VERSION 5.8 ;
BUSBITCHARS "[]" ;
DIVIDERCHAR "/" ;
UNITS
    DATABASE MICRONS 1000 ;
END UNITS

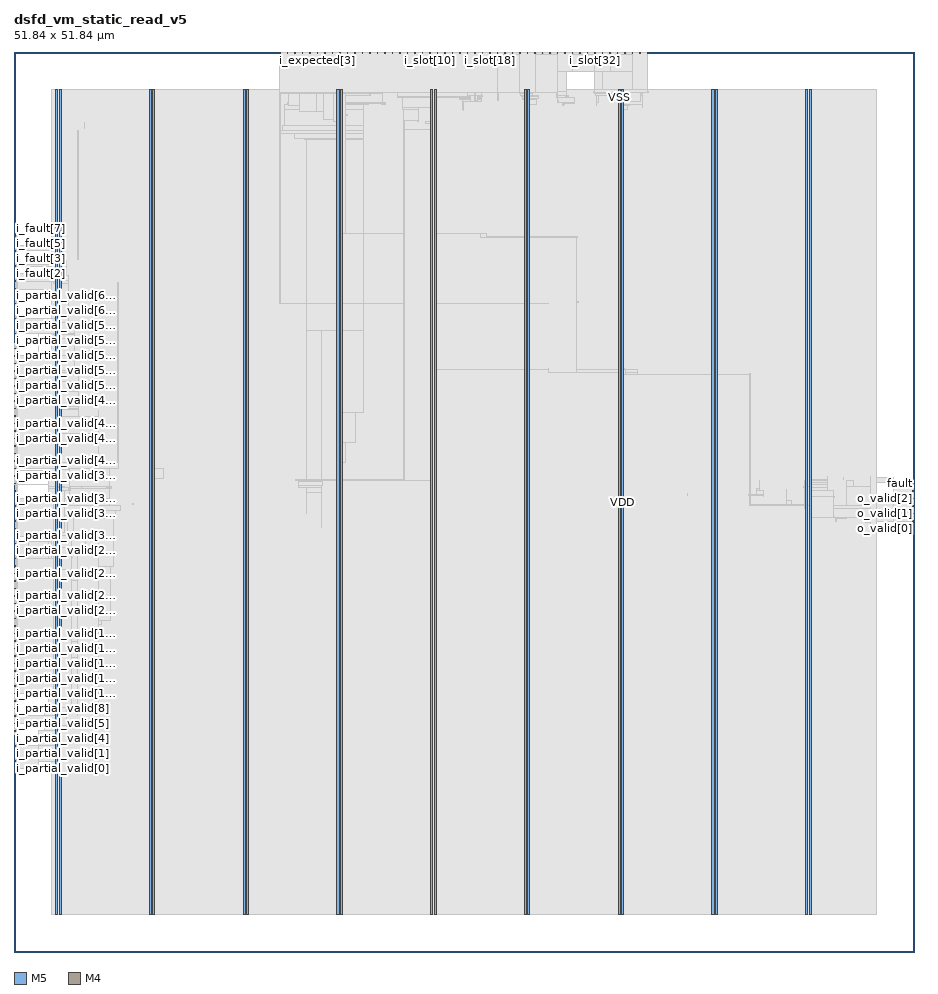
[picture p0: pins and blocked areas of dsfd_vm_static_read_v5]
MACRO dsfd_vm_static_read_v5
  FOREIGN dsfd_vm_static_read_v5 0 0 ;
  CLASS BLOCK ;
  SIZE 51.84 BY 51.84 ;
  PIN ck
    DIRECTION INPUT ;
    USE SIGNAL ;
    PORT
      LAYER M5 ;
        RECT  15.312 51.756 15.336 51.84 ;
    END
  END ck
  PIN fault
    DIRECTION OUTPUT ;
    USE SIGNAL ;
    PORT
      LAYER M4 ;
        RECT  51.756 26.976 51.84 27 ;
    END
  END fault
  PIN i_expected[0]
    DIRECTION INPUT ;
    USE SIGNAL ;
    PORT
      LAYER M5 ;
        RECT  16.176 51.756 16.2 51.84 ;
    END
  END i_expected[0]
  PIN i_expected[1]
    DIRECTION INPUT ;
    USE SIGNAL ;
    PORT
      LAYER M5 ;
        RECT  16.608 51.756 16.632 51.84 ;
    END
  END i_expected[1]
  PIN i_expected[2]
    DIRECTION INPUT ;
    USE SIGNAL ;
    PORT
      LAYER M5 ;
        RECT  17.04 51.756 17.064 51.84 ;
    END
  END i_expected[2]
  PIN i_expected[3]
    DIRECTION INPUT ;
    USE SIGNAL ;
    PORT
      LAYER M5 ;
        RECT  17.472 51.756 17.496 51.84 ;
    END
  END i_expected[3]
  PIN i_expected[4]
    DIRECTION INPUT ;
    USE SIGNAL ;
    PORT
      LAYER M5 ;
        RECT  17.904 51.756 17.928 51.84 ;
    END
  END i_expected[4]
  PIN i_expected[5]
    DIRECTION INPUT ;
    USE SIGNAL ;
    PORT
      LAYER M5 ;
        RECT  18.336 51.756 18.36 51.84 ;
    END
  END i_expected[5]
  PIN i_expected[6]
    DIRECTION INPUT ;
    USE SIGNAL ;
    PORT
      LAYER M5 ;
        RECT  18.768 51.756 18.792 51.84 ;
    END
  END i_expected[6]
  PIN i_expected[7]
    DIRECTION INPUT ;
    USE SIGNAL ;
    PORT
      LAYER M5 ;
        RECT  19.2 51.756 19.224 51.84 ;
    END
  END i_expected[7]
  PIN i_fault[0]
    DIRECTION INPUT ;
    USE SIGNAL ;
    PORT
      LAYER M4 ;
        RECT  0 38.208 0.084 38.232 ;
    END
  END i_fault[0]
  PIN i_fault[1]
    DIRECTION INPUT ;
    USE SIGNAL ;
    PORT
      LAYER M4 ;
        RECT  0 38.64 0.084 38.664 ;
    END
  END i_fault[1]
  PIN i_fault[2]
    DIRECTION INPUT ;
    USE SIGNAL ;
    PORT
      LAYER M4 ;
        RECT  0 39.072 0.084 39.096 ;
    END
  END i_fault[2]
  PIN i_fault[3]
    DIRECTION INPUT ;
    USE SIGNAL ;
    PORT
      LAYER M4 ;
        RECT  0 39.504 0.084 39.528 ;
    END
  END i_fault[3]
  PIN i_fault[4]
    DIRECTION INPUT ;
    USE SIGNAL ;
    PORT
      LAYER M4 ;
        RECT  0 39.936 0.084 39.96 ;
    END
  END i_fault[4]
  PIN i_fault[5]
    DIRECTION INPUT ;
    USE SIGNAL ;
    PORT
      LAYER M4 ;
        RECT  0 40.368 0.084 40.392 ;
    END
  END i_fault[5]
  PIN i_fault[6]
    DIRECTION INPUT ;
    USE SIGNAL ;
    PORT
      LAYER M4 ;
        RECT  0 40.8 0.084 40.824 ;
    END
  END i_fault[6]
  PIN i_fault[7]
    DIRECTION INPUT ;
    USE SIGNAL ;
    PORT
      LAYER M4 ;
        RECT  0 41.232 0.084 41.256 ;
    END
  END i_fault[7]
  PIN i_partial_valid[0]
    DIRECTION INPUT ;
    USE SIGNAL ;
    PORT
      LAYER M4 ;
        RECT  0 10.56 0.084 10.584 ;
    END
  END i_partial_valid[0]
  PIN i_partial_valid[10]
    DIRECTION INPUT ;
    USE SIGNAL ;
    PORT
      LAYER M4 ;
        RECT  0 14.88 0.084 14.904 ;
    END
  END i_partial_valid[10]
  PIN i_partial_valid[11]
    DIRECTION INPUT ;
    USE SIGNAL ;
    PORT
      LAYER M4 ;
        RECT  0 15.312 0.084 15.336 ;
    END
  END i_partial_valid[11]
  PIN i_partial_valid[12]
    DIRECTION INPUT ;
    USE SIGNAL ;
    PORT
      LAYER M4 ;
        RECT  0 15.744 0.084 15.768 ;
    END
  END i_partial_valid[12]
  PIN i_partial_valid[13]
    DIRECTION INPUT ;
    USE SIGNAL ;
    PORT
      LAYER M4 ;
        RECT  0 16.176 0.084 16.2 ;
    END
  END i_partial_valid[13]
  PIN i_partial_valid[14]
    DIRECTION INPUT ;
    USE SIGNAL ;
    PORT
      LAYER M4 ;
        RECT  0 16.608 0.084 16.632 ;
    END
  END i_partial_valid[14]
  PIN i_partial_valid[15]
    DIRECTION INPUT ;
    USE SIGNAL ;
    PORT
      LAYER M4 ;
        RECT  0 17.04 0.084 17.064 ;
    END
  END i_partial_valid[15]
  PIN i_partial_valid[16]
    DIRECTION INPUT ;
    USE SIGNAL ;
    PORT
      LAYER M4 ;
        RECT  0 17.472 0.084 17.496 ;
    END
  END i_partial_valid[16]
  PIN i_partial_valid[17]
    DIRECTION INPUT ;
    USE SIGNAL ;
    PORT
      LAYER M4 ;
        RECT  0 17.904 0.084 17.928 ;
    END
  END i_partial_valid[17]
  PIN i_partial_valid[18]
    DIRECTION INPUT ;
    USE SIGNAL ;
    PORT
      LAYER M4 ;
        RECT  0 18.336 0.084 18.36 ;
    END
  END i_partial_valid[18]
  PIN i_partial_valid[19]
    DIRECTION INPUT ;
    USE SIGNAL ;
    PORT
      LAYER M4 ;
        RECT  0 18.768 0.084 18.792 ;
    END
  END i_partial_valid[19]
  PIN i_partial_valid[1]
    DIRECTION INPUT ;
    USE SIGNAL ;
    PORT
      LAYER M4 ;
        RECT  0 10.992 0.084 11.016 ;
    END
  END i_partial_valid[1]
  PIN i_partial_valid[20]
    DIRECTION INPUT ;
    USE SIGNAL ;
    PORT
      LAYER M4 ;
        RECT  0 19.2 0.084 19.224 ;
    END
  END i_partial_valid[20]
  PIN i_partial_valid[21]
    DIRECTION INPUT ;
    USE SIGNAL ;
    PORT
      LAYER M4 ;
        RECT  0 19.632 0.084 19.656 ;
    END
  END i_partial_valid[21]
  PIN i_partial_valid[22]
    DIRECTION INPUT ;
    USE SIGNAL ;
    PORT
      LAYER M4 ;
        RECT  0 20.064 0.084 20.088 ;
    END
  END i_partial_valid[22]
  PIN i_partial_valid[23]
    DIRECTION INPUT ;
    USE SIGNAL ;
    PORT
      LAYER M4 ;
        RECT  0 20.496 0.084 20.52 ;
    END
  END i_partial_valid[23]
  PIN i_partial_valid[24]
    DIRECTION INPUT ;
    USE SIGNAL ;
    PORT
      LAYER M4 ;
        RECT  0 20.928 0.084 20.952 ;
    END
  END i_partial_valid[24]
  PIN i_partial_valid[25]
    DIRECTION INPUT ;
    USE SIGNAL ;
    PORT
      LAYER M4 ;
        RECT  0 21.36 0.084 21.384 ;
    END
  END i_partial_valid[25]
  PIN i_partial_valid[26]
    DIRECTION INPUT ;
    USE SIGNAL ;
    PORT
      LAYER M4 ;
        RECT  0 21.792 0.084 21.816 ;
    END
  END i_partial_valid[26]
  PIN i_partial_valid[27]
    DIRECTION INPUT ;
    USE SIGNAL ;
    PORT
      LAYER M4 ;
        RECT  0 22.224 0.084 22.248 ;
    END
  END i_partial_valid[27]
  PIN i_partial_valid[28]
    DIRECTION INPUT ;
    USE SIGNAL ;
    PORT
      LAYER M4 ;
        RECT  0 22.656 0.084 22.68 ;
    END
  END i_partial_valid[28]
  PIN i_partial_valid[29]
    DIRECTION INPUT ;
    USE SIGNAL ;
    PORT
      LAYER M4 ;
        RECT  0 23.088 0.084 23.112 ;
    END
  END i_partial_valid[29]
  PIN i_partial_valid[2]
    DIRECTION INPUT ;
    USE SIGNAL ;
    PORT
      LAYER M4 ;
        RECT  0 11.424 0.084 11.448 ;
    END
  END i_partial_valid[2]
  PIN i_partial_valid[30]
    DIRECTION INPUT ;
    USE SIGNAL ;
    PORT
      LAYER M4 ;
        RECT  0 23.52 0.084 23.544 ;
    END
  END i_partial_valid[30]
  PIN i_partial_valid[31]
    DIRECTION INPUT ;
    USE SIGNAL ;
    PORT
      LAYER M4 ;
        RECT  0 23.952 0.084 23.976 ;
    END
  END i_partial_valid[31]
  PIN i_partial_valid[32]
    DIRECTION INPUT ;
    USE SIGNAL ;
    PORT
      LAYER M4 ;
        RECT  0 24.384 0.084 24.408 ;
    END
  END i_partial_valid[32]
  PIN i_partial_valid[33]
    DIRECTION INPUT ;
    USE SIGNAL ;
    PORT
      LAYER M4 ;
        RECT  0 24.816 0.084 24.84 ;
    END
  END i_partial_valid[33]
  PIN i_partial_valid[34]
    DIRECTION INPUT ;
    USE SIGNAL ;
    PORT
      LAYER M4 ;
        RECT  0 25.248 0.084 25.272 ;
    END
  END i_partial_valid[34]
  PIN i_partial_valid[35]
    DIRECTION INPUT ;
    USE SIGNAL ;
    PORT
      LAYER M4 ;
        RECT  0 25.68 0.084 25.704 ;
    END
  END i_partial_valid[35]
  PIN i_partial_valid[36]
    DIRECTION INPUT ;
    USE SIGNAL ;
    PORT
      LAYER M4 ;
        RECT  0 26.112 0.084 26.136 ;
    END
  END i_partial_valid[36]
  PIN i_partial_valid[37]
    DIRECTION INPUT ;
    USE SIGNAL ;
    PORT
      LAYER M4 ;
        RECT  0 26.544 0.084 26.568 ;
    END
  END i_partial_valid[37]
  PIN i_partial_valid[38]
    DIRECTION INPUT ;
    USE SIGNAL ;
    PORT
      LAYER M4 ;
        RECT  0 26.976 0.084 27 ;
    END
  END i_partial_valid[38]
  PIN i_partial_valid[39]
    DIRECTION INPUT ;
    USE SIGNAL ;
    PORT
      LAYER M4 ;
        RECT  0 27.408 0.084 27.432 ;
    END
  END i_partial_valid[39]
  PIN i_partial_valid[3]
    DIRECTION INPUT ;
    USE SIGNAL ;
    PORT
      LAYER M4 ;
        RECT  0 11.856 0.084 11.88 ;
    END
  END i_partial_valid[3]
  PIN i_partial_valid[40]
    DIRECTION INPUT ;
    USE SIGNAL ;
    PORT
      LAYER M4 ;
        RECT  0 27.84 0.084 27.864 ;
    END
  END i_partial_valid[40]
  PIN i_partial_valid[41]
    DIRECTION INPUT ;
    USE SIGNAL ;
    PORT
      LAYER M4 ;
        RECT  0 28.272 0.084 28.296 ;
    END
  END i_partial_valid[41]
  PIN i_partial_valid[42]
    DIRECTION INPUT ;
    USE SIGNAL ;
    PORT
      LAYER M4 ;
        RECT  0 28.704 0.084 28.728 ;
    END
  END i_partial_valid[42]
  PIN i_partial_valid[43]
    DIRECTION INPUT ;
    USE SIGNAL ;
    PORT
      LAYER M4 ;
        RECT  0 29.136 0.084 29.16 ;
    END
  END i_partial_valid[43]
  PIN i_partial_valid[44]
    DIRECTION INPUT ;
    USE SIGNAL ;
    PORT
      LAYER M4 ;
        RECT  0 29.568 0.084 29.592 ;
    END
  END i_partial_valid[44]
  PIN i_partial_valid[45]
    DIRECTION INPUT ;
    USE SIGNAL ;
    PORT
      LAYER M4 ;
        RECT  0 30 0.084 30.024 ;
    END
  END i_partial_valid[45]
  PIN i_partial_valid[46]
    DIRECTION INPUT ;
    USE SIGNAL ;
    PORT
      LAYER M4 ;
        RECT  0 30.432 0.084 30.456 ;
    END
  END i_partial_valid[46]
  PIN i_partial_valid[47]
    DIRECTION INPUT ;
    USE SIGNAL ;
    PORT
      LAYER M4 ;
        RECT  0 30.864 0.084 30.888 ;
    END
  END i_partial_valid[47]
  PIN i_partial_valid[48]
    DIRECTION INPUT ;
    USE SIGNAL ;
    PORT
      LAYER M4 ;
        RECT  0 31.296 0.084 31.32 ;
    END
  END i_partial_valid[48]
  PIN i_partial_valid[49]
    DIRECTION INPUT ;
    USE SIGNAL ;
    PORT
      LAYER M4 ;
        RECT  0 31.728 0.084 31.752 ;
    END
  END i_partial_valid[49]
  PIN i_partial_valid[4]
    DIRECTION INPUT ;
    USE SIGNAL ;
    PORT
      LAYER M4 ;
        RECT  0 12.288 0.084 12.312 ;
    END
  END i_partial_valid[4]
  PIN i_partial_valid[50]
    DIRECTION INPUT ;
    USE SIGNAL ;
    PORT
      LAYER M4 ;
        RECT  0 32.16 0.084 32.184 ;
    END
  END i_partial_valid[50]
  PIN i_partial_valid[51]
    DIRECTION INPUT ;
    USE SIGNAL ;
    PORT
      LAYER M4 ;
        RECT  0 32.592 0.084 32.616 ;
    END
  END i_partial_valid[51]
  PIN i_partial_valid[52]
    DIRECTION INPUT ;
    USE SIGNAL ;
    PORT
      LAYER M4 ;
        RECT  0 33.024 0.084 33.048 ;
    END
  END i_partial_valid[52]
  PIN i_partial_valid[53]
    DIRECTION INPUT ;
    USE SIGNAL ;
    PORT
      LAYER M4 ;
        RECT  0 33.456 0.084 33.48 ;
    END
  END i_partial_valid[53]
  PIN i_partial_valid[54]
    DIRECTION INPUT ;
    USE SIGNAL ;
    PORT
      LAYER M4 ;
        RECT  0 33.888 0.084 33.912 ;
    END
  END i_partial_valid[54]
  PIN i_partial_valid[55]
    DIRECTION INPUT ;
    USE SIGNAL ;
    PORT
      LAYER M4 ;
        RECT  0 34.32 0.084 34.344 ;
    END
  END i_partial_valid[55]
  PIN i_partial_valid[56]
    DIRECTION INPUT ;
    USE SIGNAL ;
    PORT
      LAYER M4 ;
        RECT  0 34.752 0.084 34.776 ;
    END
  END i_partial_valid[56]
  PIN i_partial_valid[57]
    DIRECTION INPUT ;
    USE SIGNAL ;
    PORT
      LAYER M4 ;
        RECT  0 35.184 0.084 35.208 ;
    END
  END i_partial_valid[57]
  PIN i_partial_valid[58]
    DIRECTION INPUT ;
    USE SIGNAL ;
    PORT
      LAYER M4 ;
        RECT  0 35.616 0.084 35.64 ;
    END
  END i_partial_valid[58]
  PIN i_partial_valid[59]
    DIRECTION INPUT ;
    USE SIGNAL ;
    PORT
      LAYER M4 ;
        RECT  0 36.048 0.084 36.072 ;
    END
  END i_partial_valid[59]
  PIN i_partial_valid[5]
    DIRECTION INPUT ;
    USE SIGNAL ;
    PORT
      LAYER M4 ;
        RECT  0 12.72 0.084 12.744 ;
    END
  END i_partial_valid[5]
  PIN i_partial_valid[60]
    DIRECTION INPUT ;
    USE SIGNAL ;
    PORT
      LAYER M4 ;
        RECT  0 36.48 0.084 36.504 ;
    END
  END i_partial_valid[60]
  PIN i_partial_valid[61]
    DIRECTION INPUT ;
    USE SIGNAL ;
    PORT
      LAYER M4 ;
        RECT  0 36.912 0.084 36.936 ;
    END
  END i_partial_valid[61]
  PIN i_partial_valid[62]
    DIRECTION INPUT ;
    USE SIGNAL ;
    PORT
      LAYER M4 ;
        RECT  0 37.344 0.084 37.368 ;
    END
  END i_partial_valid[62]
  PIN i_partial_valid[63]
    DIRECTION INPUT ;
    USE SIGNAL ;
    PORT
      LAYER M4 ;
        RECT  0 37.776 0.084 37.8 ;
    END
  END i_partial_valid[63]
  PIN i_partial_valid[6]
    DIRECTION INPUT ;
    USE SIGNAL ;
    PORT
      LAYER M4 ;
        RECT  0 13.152 0.084 13.176 ;
    END
  END i_partial_valid[6]
  PIN i_partial_valid[7]
    DIRECTION INPUT ;
    USE SIGNAL ;
    PORT
      LAYER M4 ;
        RECT  0 13.584 0.084 13.608 ;
    END
  END i_partial_valid[7]
  PIN i_partial_valid[8]
    DIRECTION INPUT ;
    USE SIGNAL ;
    PORT
      LAYER M4 ;
        RECT  0 14.016 0.084 14.04 ;
    END
  END i_partial_valid[8]
  PIN i_partial_valid[9]
    DIRECTION INPUT ;
    USE SIGNAL ;
    PORT
      LAYER M4 ;
        RECT  0 14.448 0.084 14.472 ;
    END
  END i_partial_valid[9]
  PIN i_slot[0]
    DIRECTION INPUT ;
    USE SIGNAL ;
    PORT
      LAYER M5 ;
        RECT  19.632 51.756 19.656 51.84 ;
    END
  END i_slot[0]
  PIN i_slot[10]
    DIRECTION INPUT ;
    USE SIGNAL ;
    PORT
      LAYER M5 ;
        RECT  23.952 51.756 23.976 51.84 ;
    END
  END i_slot[10]
  PIN i_slot[11]
    DIRECTION INPUT ;
    USE SIGNAL ;
    PORT
      LAYER M5 ;
        RECT  24.384 51.756 24.408 51.84 ;
    END
  END i_slot[11]
  PIN i_slot[12]
    DIRECTION INPUT ;
    USE SIGNAL ;
    PORT
      LAYER M5 ;
        RECT  24.816 51.756 24.84 51.84 ;
    END
  END i_slot[12]
  PIN i_slot[13]
    DIRECTION INPUT ;
    USE SIGNAL ;
    PORT
      LAYER M5 ;
        RECT  25.248 51.756 25.272 51.84 ;
    END
  END i_slot[13]
  PIN i_slot[14]
    DIRECTION INPUT ;
    USE SIGNAL ;
    PORT
      LAYER M5 ;
        RECT  25.68 51.756 25.704 51.84 ;
    END
  END i_slot[14]
  PIN i_slot[15]
    DIRECTION INPUT ;
    USE SIGNAL ;
    PORT
      LAYER M5 ;
        RECT  26.112 51.756 26.136 51.84 ;
    END
  END i_slot[15]
  PIN i_slot[16]
    DIRECTION INPUT ;
    USE SIGNAL ;
    PORT
      LAYER M5 ;
        RECT  26.544 51.756 26.568 51.84 ;
    END
  END i_slot[16]
  PIN i_slot[17]
    DIRECTION INPUT ;
    USE SIGNAL ;
    PORT
      LAYER M5 ;
        RECT  26.976 51.756 27 51.84 ;
    END
  END i_slot[17]
  PIN i_slot[18]
    DIRECTION INPUT ;
    USE SIGNAL ;
    PORT
      LAYER M5 ;
        RECT  27.408 51.756 27.432 51.84 ;
    END
  END i_slot[18]
  PIN i_slot[19]
    DIRECTION INPUT ;
    USE SIGNAL ;
    PORT
      LAYER M5 ;
        RECT  27.84 51.756 27.864 51.84 ;
    END
  END i_slot[19]
  PIN i_slot[1]
    DIRECTION INPUT ;
    USE SIGNAL ;
    PORT
      LAYER M5 ;
        RECT  20.064 51.756 20.088 51.84 ;
    END
  END i_slot[1]
  PIN i_slot[20]
    DIRECTION INPUT ;
    USE SIGNAL ;
    PORT
      LAYER M5 ;
        RECT  28.272 51.756 28.296 51.84 ;
    END
  END i_slot[20]
  PIN i_slot[21]
    DIRECTION INPUT ;
    USE SIGNAL ;
    PORT
      LAYER M5 ;
        RECT  28.704 51.756 28.728 51.84 ;
    END
  END i_slot[21]
  PIN i_slot[22]
    DIRECTION INPUT ;
    USE SIGNAL ;
    PORT
      LAYER M5 ;
        RECT  29.136 51.756 29.16 51.84 ;
    END
  END i_slot[22]
  PIN i_slot[23]
    DIRECTION INPUT ;
    USE SIGNAL ;
    PORT
      LAYER M5 ;
        RECT  29.568 51.756 29.592 51.84 ;
    END
  END i_slot[23]
  PIN i_slot[24]
    DIRECTION INPUT ;
    USE SIGNAL ;
    PORT
      LAYER M5 ;
        RECT  30 51.756 30.024 51.84 ;
    END
  END i_slot[24]
  PIN i_slot[25]
    DIRECTION INPUT ;
    USE SIGNAL ;
    PORT
      LAYER M5 ;
        RECT  30.432 51.756 30.456 51.84 ;
    END
  END i_slot[25]
  PIN i_slot[26]
    DIRECTION INPUT ;
    USE SIGNAL ;
    PORT
      LAYER M5 ;
        RECT  30.864 51.756 30.888 51.84 ;
    END
  END i_slot[26]
  PIN i_slot[27]
    DIRECTION INPUT ;
    USE SIGNAL ;
    PORT
      LAYER M5 ;
        RECT  31.296 51.756 31.32 51.84 ;
    END
  END i_slot[27]
  PIN i_slot[28]
    DIRECTION INPUT ;
    USE SIGNAL ;
    PORT
      LAYER M5 ;
        RECT  31.728 51.756 31.752 51.84 ;
    END
  END i_slot[28]
  PIN i_slot[29]
    DIRECTION INPUT ;
    USE SIGNAL ;
    PORT
      LAYER M5 ;
        RECT  32.16 51.756 32.184 51.84 ;
    END
  END i_slot[29]
  PIN i_slot[2]
    DIRECTION INPUT ;
    USE SIGNAL ;
    PORT
      LAYER M5 ;
        RECT  20.496 51.756 20.52 51.84 ;
    END
  END i_slot[2]
  PIN i_slot[30]
    DIRECTION INPUT ;
    USE SIGNAL ;
    PORT
      LAYER M5 ;
        RECT  32.592 51.756 32.616 51.84 ;
    END
  END i_slot[30]
  PIN i_slot[31]
    DIRECTION INPUT ;
    USE SIGNAL ;
    PORT
      LAYER M5 ;
        RECT  33.024 51.756 33.048 51.84 ;
    END
  END i_slot[31]
  PIN i_slot[32]
    DIRECTION INPUT ;
    USE SIGNAL ;
    PORT
      LAYER M5 ;
        RECT  33.456 51.756 33.48 51.84 ;
    END
  END i_slot[32]
  PIN i_slot[33]
    DIRECTION INPUT ;
    USE SIGNAL ;
    PORT
      LAYER M5 ;
        RECT  33.888 51.756 33.912 51.84 ;
    END
  END i_slot[33]
  PIN i_slot[34]
    DIRECTION INPUT ;
    USE SIGNAL ;
    PORT
      LAYER M5 ;
        RECT  34.32 51.756 34.344 51.84 ;
    END
  END i_slot[34]
  PIN i_slot[35]
    DIRECTION INPUT ;
    USE SIGNAL ;
    PORT
      LAYER M5 ;
        RECT  34.752 51.756 34.776 51.84 ;
    END
  END i_slot[35]
  PIN i_slot[36]
    DIRECTION INPUT ;
    USE SIGNAL ;
    PORT
      LAYER M5 ;
        RECT  35.184 51.756 35.208 51.84 ;
    END
  END i_slot[36]
  PIN i_slot[37]
    DIRECTION INPUT ;
    USE SIGNAL ;
    PORT
      LAYER M5 ;
        RECT  35.616 51.756 35.64 51.84 ;
    END
  END i_slot[37]
  PIN i_slot[38]
    DIRECTION INPUT ;
    USE SIGNAL ;
    PORT
      LAYER M5 ;
        RECT  36.048 51.756 36.072 51.84 ;
    END
  END i_slot[38]
  PIN i_slot[39]
    DIRECTION INPUT ;
    USE SIGNAL ;
    PORT
      LAYER M5 ;
        RECT  36.48 51.756 36.504 51.84 ;
    END
  END i_slot[39]
  PIN i_slot[3]
    DIRECTION INPUT ;
    USE SIGNAL ;
    PORT
      LAYER M5 ;
        RECT  20.928 51.756 20.952 51.84 ;
    END
  END i_slot[3]
  PIN i_slot[4]
    DIRECTION INPUT ;
    USE SIGNAL ;
    PORT
      LAYER M5 ;
        RECT  21.36 51.756 21.384 51.84 ;
    END
  END i_slot[4]
  PIN i_slot[5]
    DIRECTION INPUT ;
    USE SIGNAL ;
    PORT
      LAYER M5 ;
        RECT  21.792 51.756 21.816 51.84 ;
    END
  END i_slot[5]
  PIN i_slot[6]
    DIRECTION INPUT ;
    USE SIGNAL ;
    PORT
      LAYER M5 ;
        RECT  22.224 51.756 22.248 51.84 ;
    END
  END i_slot[6]
  PIN i_slot[7]
    DIRECTION INPUT ;
    USE SIGNAL ;
    PORT
      LAYER M5 ;
        RECT  22.656 51.756 22.68 51.84 ;
    END
  END i_slot[7]
  PIN i_slot[8]
    DIRECTION INPUT ;
    USE SIGNAL ;
    PORT
      LAYER M5 ;
        RECT  23.088 51.756 23.112 51.84 ;
    END
  END i_slot[8]
  PIN i_slot[9]
    DIRECTION INPUT ;
    USE SIGNAL ;
    PORT
      LAYER M5 ;
        RECT  23.52 51.756 23.544 51.84 ;
    END
  END i_slot[9]
  PIN o_valid[0]
    DIRECTION OUTPUT ;
    USE SIGNAL ;
    PORT
      LAYER M4 ;
        RECT  51.756 24.816 51.84 24.84 ;
    END
  END o_valid[0]
  PIN o_valid[1]
    DIRECTION OUTPUT ;
    USE SIGNAL ;
    PORT
      LAYER M4 ;
        RECT  51.756 25.248 51.84 25.272 ;
    END
  END o_valid[1]
  PIN o_valid[2]
    DIRECTION OUTPUT ;
    USE SIGNAL ;
    PORT
      LAYER M4 ;
        RECT  51.756 25.68 51.84 25.704 ;
    END
  END o_valid[2]
  PIN o_valid[3]
    DIRECTION OUTPUT ;
    USE SIGNAL ;
    PORT
      LAYER M4 ;
        RECT  51.756 26.112 51.84 26.136 ;
    END
  END o_valid[3]
  PIN o_valid[4]
    DIRECTION OUTPUT ;
    USE SIGNAL ;
    PORT
      LAYER M4 ;
        RECT  51.756 26.544 51.84 26.568 ;
    END
  END o_valid[4]
  PIN rst_n
    DIRECTION INPUT ;
    USE SIGNAL ;
    PORT
      LAYER M5 ;
        RECT  15.744 51.756 15.768 51.84 ;
    END
  END rst_n
  PIN VDD
    DIRECTION INOUT ;
    USE POWER ;
    PORT
      LAYER M5 ;
        RECT  45.792 2.151 45.912 49.689 ;
        RECT  40.392 2.151 40.512 49.689 ;
        RECT  34.992 2.151 35.112 49.689 ;
        RECT  29.592 2.151 29.712 49.689 ;
        RECT  24.192 2.151 24.312 49.689 ;
        RECT  18.792 2.151 18.912 49.689 ;
        RECT  13.392 2.151 13.512 49.689 ;
        RECT  7.992 2.151 8.112 49.689 ;
        RECT  2.592 2.151 2.712 49.689 ;
    END
  END VDD
  PIN VSS
    DIRECTION INOUT ;
    USE GROUND ;
    PORT
      LAYER M5 ;
        RECT  45.6 2.137 45.72 49.703 ;
        RECT  40.2 2.137 40.32 49.703 ;
        RECT  34.8 2.137 34.92 49.703 ;
        RECT  29.4 2.137 29.52 49.703 ;
        RECT  24 2.137 24.12 49.703 ;
        RECT  18.6 2.137 18.72 49.703 ;
        RECT  13.2 2.137 13.32 49.703 ;
        RECT  7.8 2.137 7.92 49.703 ;
        RECT  2.4 2.137 2.52 49.703 ;
    END
  END VSS
  # OT_OBS_CLOSED layer=M5 d_um=1.536 added=21
  OBS
    LAYER RVTN ;
     RECT  2.16 2.16 49.68 2.295 ;
     RECT  2.16 2.565 49.68 2.835 ;
     RECT  2.16 3.105 49.68 3.375 ;
     RECT  2.16 3.645 49.68 3.915 ;
     RECT  2.16 4.185 49.68 4.455 ;
     RECT  2.16 4.725 49.68 4.995 ;
     RECT  2.16 5.265 49.68 5.535 ;
     RECT  2.16 5.805 49.68 6.075 ;
     RECT  2.16 6.345 49.68 6.615 ;
     RECT  2.16 6.885 49.68 7.155 ;
     RECT  2.16 7.425 49.68 7.695 ;
     RECT  2.16 7.965 49.68 8.235 ;
     RECT  2.16 8.505 49.68 8.775 ;
     RECT  2.16 9.045 49.68 9.315 ;
     RECT  2.16 9.585 49.68 9.855 ;
     RECT  2.16 10.125 49.68 10.395 ;
     RECT  2.16 10.665 49.68 10.935 ;
     RECT  2.16 11.205 49.68 11.475 ;
     RECT  2.16 11.745 49.68 12.015 ;
     RECT  2.16 12.285 49.68 12.555 ;
     RECT  2.16 12.825 49.68 13.095 ;
     RECT  2.16 13.365 49.68 13.635 ;
     RECT  2.16 13.905 49.68 14.175 ;
     RECT  2.16 14.445 49.68 14.715 ;
     RECT  2.16 14.985 49.68 15.255 ;
     RECT  2.16 15.525 49.68 15.795 ;
     RECT  2.16 16.065 49.68 16.335 ;
     RECT  2.16 16.605 49.68 16.875 ;
     RECT  2.16 17.145 49.68 17.415 ;
     RECT  2.16 17.685 49.68 17.955 ;
     RECT  2.16 18.225 49.68 18.495 ;
     RECT  2.16 18.765 49.68 19.035 ;
     RECT  2.16 19.305 49.68 19.575 ;
     RECT  2.16 19.845 49.68 20.115 ;
     RECT  2.16 20.385 49.68 20.655 ;
     RECT  2.16 20.925 49.68 21.195 ;
     RECT  2.16 21.465 49.68 21.735 ;
     RECT  2.16 22.005 49.68 22.275 ;
     RECT  2.16 22.545 49.68 22.815 ;
     RECT  2.16 23.085 49.68 23.355 ;
     RECT  2.16 23.625 49.68 23.895 ;
     RECT  2.16 24.165 49.68 24.435 ;
     RECT  2.16 24.705 49.68 24.975 ;
     RECT  2.16 25.245 49.68 25.515 ;
     RECT  2.16 25.785 49.68 26.055 ;
     RECT  2.16 26.325 49.68 26.595 ;
     RECT  2.16 26.865 49.68 27.135 ;
     RECT  2.16 27.405 49.68 27.675 ;
     RECT  2.16 27.945 49.68 28.215 ;
     RECT  2.16 28.485 49.68 28.755 ;
     RECT  2.16 29.025 49.68 29.295 ;
     RECT  2.16 29.565 49.68 29.835 ;
     RECT  2.16 30.105 49.68 30.375 ;
     RECT  2.16 30.645 49.68 30.915 ;
     RECT  2.16 31.185 49.68 31.455 ;
     RECT  2.16 31.725 49.68 31.995 ;
     RECT  2.16 32.265 49.68 32.535 ;
     RECT  2.16 32.805 49.68 33.075 ;
     RECT  2.16 33.345 49.68 33.615 ;
     RECT  2.16 33.885 49.68 34.155 ;
     RECT  2.16 34.425 49.68 34.695 ;
     RECT  2.16 34.965 49.68 35.235 ;
     RECT  2.16 35.505 49.68 35.775 ;
     RECT  2.16 36.045 49.68 36.315 ;
     RECT  2.16 36.585 49.68 36.855 ;
     RECT  2.16 37.125 49.68 37.395 ;
     RECT  2.16 37.665 49.68 37.935 ;
     RECT  2.16 38.205 49.68 38.475 ;
     RECT  2.16 38.745 49.68 39.015 ;
     RECT  2.16 39.285 49.68 39.555 ;
     RECT  2.16 39.825 49.68 40.095 ;
     RECT  2.16 40.365 49.68 40.635 ;
     RECT  2.16 40.905 49.68 41.175 ;
     RECT  2.16 41.445 49.68 41.715 ;
     RECT  2.16 41.985 49.68 42.255 ;
     RECT  2.16 42.525 49.68 42.795 ;
     RECT  2.16 43.065 49.68 43.335 ;
     RECT  2.16 43.605 49.68 43.875 ;
     RECT  2.16 44.145 49.68 44.415 ;
     RECT  2.16 44.685 49.68 44.955 ;
     RECT  2.16 45.225 49.68 45.495 ;
     RECT  2.16 45.765 49.68 46.035 ;
     RECT  2.16 46.305 49.68 46.575 ;
     RECT  2.16 46.845 49.68 47.115 ;
     RECT  2.16 47.385 49.68 47.655 ;
     RECT  2.16 47.925 49.68 48.195 ;
     RECT  2.16 48.465 49.68 48.735 ;
     RECT  2.16 49.005 49.68 49.275 ;
     RECT  2.16 49.545 49.68 49.68 ;
    LAYER RVTP ;
     RECT  2.16 2.295 49.68 2.565 ;
     RECT  2.16 2.835 49.68 3.105 ;
     RECT  2.16 3.375 49.68 3.645 ;
     RECT  2.16 3.915 49.68 4.185 ;
     RECT  2.16 4.455 49.68 4.725 ;
     RECT  2.16 4.995 49.68 5.265 ;
     RECT  2.16 5.535 49.68 5.805 ;
     RECT  2.16 6.075 49.68 6.345 ;
     RECT  2.16 6.615 49.68 6.885 ;
     RECT  2.16 7.155 49.68 7.425 ;
     RECT  2.16 7.695 49.68 7.965 ;
     RECT  2.16 8.235 49.68 8.505 ;
     RECT  2.16 8.775 49.68 9.045 ;
     RECT  2.16 9.315 49.68 9.585 ;
     RECT  2.16 9.855 49.68 10.125 ;
     RECT  2.16 10.395 49.68 10.665 ;
     RECT  2.16 10.935 49.68 11.205 ;
     RECT  2.16 11.475 49.68 11.745 ;
     RECT  2.16 12.015 49.68 12.285 ;
     RECT  2.16 12.555 49.68 12.825 ;
     RECT  2.16 13.095 49.68 13.365 ;
     RECT  2.16 13.635 49.68 13.905 ;
     RECT  2.16 14.175 49.68 14.445 ;
     RECT  2.16 14.715 49.68 14.985 ;
     RECT  2.16 15.255 49.68 15.525 ;
     RECT  2.16 15.795 49.68 16.065 ;
     RECT  2.16 16.335 49.68 16.605 ;
     RECT  2.16 16.875 49.68 17.145 ;
     RECT  2.16 17.415 49.68 17.685 ;
     RECT  2.16 17.955 49.68 18.225 ;
     RECT  2.16 18.495 49.68 18.765 ;
     RECT  2.16 19.035 49.68 19.305 ;
     RECT  2.16 19.575 49.68 19.845 ;
     RECT  2.16 20.115 49.68 20.385 ;
     RECT  2.16 20.655 49.68 20.925 ;
     RECT  2.16 21.195 49.68 21.465 ;
     RECT  2.16 21.735 49.68 22.005 ;
     RECT  2.16 22.275 49.68 22.545 ;
     RECT  2.16 22.815 49.68 23.085 ;
     RECT  2.16 23.355 49.68 23.625 ;
     RECT  2.16 23.895 49.68 24.165 ;
     RECT  2.16 24.435 49.68 24.705 ;
     RECT  2.16 24.975 49.68 25.245 ;
     RECT  2.16 25.515 49.68 25.785 ;
     RECT  2.16 26.055 49.68 26.325 ;
     RECT  2.16 26.595 49.68 26.865 ;
     RECT  2.16 27.135 49.68 27.405 ;
     RECT  2.16 27.675 49.68 27.945 ;
     RECT  2.16 28.215 49.68 28.485 ;
     RECT  2.16 28.755 49.68 29.025 ;
     RECT  2.16 29.295 49.68 29.565 ;
     RECT  2.16 29.835 49.68 30.105 ;
     RECT  2.16 30.375 49.68 30.645 ;
     RECT  2.16 30.915 49.68 31.185 ;
     RECT  2.16 31.455 49.68 31.725 ;
     RECT  2.16 31.995 49.68 32.265 ;
     RECT  2.16 32.535 49.68 32.805 ;
     RECT  2.16 33.075 49.68 33.345 ;
     RECT  2.16 33.615 49.68 33.885 ;
     RECT  2.16 34.155 49.68 34.425 ;
     RECT  2.16 34.695 49.68 34.965 ;
     RECT  2.16 35.235 49.68 35.505 ;
     RECT  2.16 35.775 49.68 36.045 ;
     RECT  2.16 36.315 49.68 36.585 ;
     RECT  2.16 36.855 49.68 37.125 ;
     RECT  2.16 37.395 49.68 37.665 ;
     RECT  2.16 37.935 49.68 38.205 ;
     RECT  2.16 38.475 49.68 38.745 ;
     RECT  2.16 39.015 49.68 39.285 ;
     RECT  2.16 39.555 49.68 39.825 ;
     RECT  2.16 40.095 49.68 40.365 ;
     RECT  2.16 40.635 49.68 40.905 ;
     RECT  2.16 41.175 49.68 41.445 ;
     RECT  2.16 41.715 49.68 41.985 ;
     RECT  2.16 42.255 49.68 42.525 ;
     RECT  2.16 42.795 49.68 43.065 ;
     RECT  2.16 43.335 49.68 43.605 ;
     RECT  2.16 43.875 49.68 44.145 ;
     RECT  2.16 44.415 49.68 44.685 ;
     RECT  2.16 44.955 49.68 45.225 ;
     RECT  2.16 45.495 49.68 45.765 ;
     RECT  2.16 46.035 49.68 46.305 ;
     RECT  2.16 46.575 49.68 46.845 ;
     RECT  2.16 47.115 49.68 47.385 ;
     RECT  2.16 47.655 49.68 47.925 ;
     RECT  2.16 48.195 49.68 48.465 ;
     RECT  2.16 48.735 49.68 49.005 ;
     RECT  2.16 49.275 49.68 49.545 ;
    LAYER M1 ;
     RECT  2.16 2.151 49.68 49.689 ;
    LAYER M2 ;
     RECT  0.031 22.05 0.103 22.068 ;
     RECT  0.067 23.256 0.103 23.274 ;
     RECT  0.067 30.186 0.103 30.204 ;
     RECT  0.103 22.05 0.139 23.346 ;
     RECT  0.103 39.6 0.139 39.618 ;
     RECT  0.103 40.41 0.139 40.428 ;
     RECT  0.103 32.472 0.175 32.49 ;
     RECT  0.139 22.05 0.823 23.652 ;
     RECT  0.103 31.122 1.399 31.14 ;
     RECT  0.103 29.502 1.435 30.204 ;
     RECT  1.399 30.96 1.435 31.14 ;
     RECT  0.067 20.826 1.975 20.844 ;
     RECT  0.823 21.636 1.975 23.652 ;
     RECT  0.139 19.89 2.011 19.908 ;
     RECT  1.975 20.826 2.011 23.652 ;
     RECT  1.399 12.762 2.16 12.78 ;
     RECT  1.723 14.076 2.16 14.094 ;
     RECT  1.975 14.886 2.16 14.904 ;
     RECT  0.103 18.846 2.16 18.864 ;
     RECT  2.011 19.89 2.16 23.652 ;
     RECT  0.175 26.1 2.16 26.118 ;
     RECT  0.031 26.91 2.16 26.928 ;
     RECT  0.139 27.72 2.16 27.738 ;
     RECT  1.435 29.502 2.16 31.14 ;
     RECT  0.175 31.968 2.16 32.49 ;
     RECT  0.103 34.164 2.16 34.182 ;
     RECT  0.103 36.36 2.16 36.378 ;
     RECT  0.103 38.142 2.16 38.7 ;
     RECT  0.139 39.492 2.16 39.618 ;
     RECT  0.139 40.41 2.16 40.698 ;
     RECT  2.16 2.151 49.68 49.689 ;
     RECT  49.68 27.036 50.675 27.324 ;
     RECT  49.68 24.786 50.711 26.244 ;
     RECT  50.675 27.036 50.711 27.054 ;
    LAYER M3 ;
     RECT  2.415 2.143 2.505 2.413 ;
     RECT  7.815 2.143 7.905 2.413 ;
     RECT  13.215 2.143 13.305 2.413 ;
     RECT  18.615 2.143 18.705 2.413 ;
     RECT  24.015 2.143 24.105 2.413 ;
     RECT  29.415 2.143 29.505 2.413 ;
     RECT  34.815 2.143 34.905 2.413 ;
     RECT  40.215 2.143 40.305 2.413 ;
     RECT  45.615 2.143 45.705 2.413 ;
     RECT  1.404 10.555 1.422 10.987 ;
     RECT  2.415 2.413 2.697 10.987 ;
     RECT  0.108 12.283 0.126 12.523 ;
     RECT  1.404 10.987 2.697 12.785 ;
     RECT  1.728 12.785 2.697 12.901 ;
     RECT  1.728 12.901 3.006 13.085 ;
     RECT  0.036 12.523 0.126 14.011 ;
     RECT  1.728 13.085 2.826 14.099 ;
     RECT  1.98 14.099 2.826 14.141 ;
     RECT  0.036 14.011 0.162 14.443 ;
     RECT  0.036 14.443 0.198 14.573 ;
     RECT  1.98 14.141 2.697 14.909 ;
     RECT  2.304 14.909 2.697 15.061 ;
     RECT  2.304 15.061 2.79 15.755 ;
     RECT  2.34 15.755 2.79 16.141 ;
     RECT  0.036 14.573 0.162 16.171 ;
     RECT  2.34 16.141 2.898 16.603 ;
     RECT  2.016 16.603 2.898 16.951 ;
     RECT  3.636 13.603 3.654 16.951 ;
     RECT  2.016 16.951 3.654 17.899 ;
     RECT  4.86 13.639 4.878 18.841 ;
     RECT  4.86 18.841 5.022 19.111 ;
     RECT  0.036 16.171 0.846 19.913 ;
     RECT  0.036 19.913 0.09 20.849 ;
     RECT  1.98 17.899 3.654 21.389 ;
     RECT  0.828 19.913 0.846 21.659 ;
     RECT  0.036 20.849 0.054 22.073 ;
     RECT  4.86 19.111 5.562 22.207 ;
     RECT  2.304 21.389 3.654 23.161 ;
     RECT  0.108 22.783 0.126 23.251 ;
     RECT  0.072 23.251 0.126 23.629 ;
     RECT  2.304 23.161 4.122 23.899 ;
     RECT  4.86 22.207 5.706 23.899 ;
     RECT  49.32 24.601 49.338 24.745 ;
     RECT  2.304 23.899 5.706 24.943 ;
     RECT  47.34 24.781 47.358 24.979 ;
     RECT  47.34 24.979 47.97 25.015 ;
     RECT  47.34 25.015 48.042 25.045 ;
     RECT  47.196 25.045 48.042 25.051 ;
     RECT  49.068 24.745 49.338 25.051 ;
     RECT  2.304 24.943 5.85 25.411 ;
     RECT  45.615 2.413 45.897 25.519 ;
     RECT  47.196 25.051 49.338 25.519 ;
     RECT  45.615 25.519 49.338 25.531 ;
     RECT  2.304 25.411 6.138 25.745 ;
     RECT  45.54 25.531 49.338 25.745 ;
     RECT  43.92 25.717 43.938 25.753 ;
     RECT  44.748 25.717 44.766 25.753 ;
     RECT  43.92 25.753 44.766 25.757 ;
     RECT  45.54 25.745 47.178 25.757 ;
     RECT  6.84 25.753 6.858 25.853 ;
     RECT  44.496 25.757 44.766 26.015 ;
     RECT  0.072 23.629 0.162 26.095 ;
     RECT  2.304 25.745 5.49 26.107 ;
     RECT  50.688 24.781 50.706 26.249 ;
     RECT  42.372 26.257 42.39 26.293 ;
     RECT  43.164 26.257 43.182 26.293 ;
     RECT  42.372 26.293 43.182 26.333 ;
     RECT  38.772 26.293 38.79 26.429 ;
     RECT  16.848 25.249 16.866 26.491 ;
     RECT  17.712 24.439 17.73 26.491 ;
     RECT  42.768 26.333 43.182 26.555 ;
     RECT  45.615 25.757 47.178 26.591 ;
     RECT  44.496 26.015 44.514 26.627 ;
     RECT  1.98 26.107 5.49 26.671 ;
     RECT  42.768 26.555 42.93 26.699 ;
     RECT  16.848 26.491 17.73 26.761 ;
     RECT  45.615 26.591 46.854 26.779 ;
     RECT  1.98 26.671 5.634 26.789 ;
     RECT  1.98 26.789 5.562 26.813 ;
     RECT  47.952 25.745 49.338 26.825 ;
     RECT  16.38 26.761 17.73 26.869 ;
     RECT  0.072 26.095 0.198 26.905 ;
     RECT  45.54 26.779 46.854 26.905 ;
     RECT  50.652 26.539 50.67 26.971 ;
     RECT  45.504 26.905 46.854 27.059 ;
     RECT  50.652 26.971 50.706 27.059 ;
     RECT  16.38 26.869 17.766 27.095 ;
     RECT  45.54 27.059 46.854 27.131 ;
     RECT  47.952 26.825 48.366 27.131 ;
     RECT  16.38 27.095 17.73 27.163 ;
     RECT  42.912 26.699 42.93 27.167 ;
     RECT  16.236 27.163 17.73 27.203 ;
     RECT  45.615 27.131 46.854 27.203 ;
     RECT  7.815 2.413 8.097 27.301 ;
     RECT  47.772 27.211 47.79 27.329 ;
     RECT  50.652 27.059 50.67 27.329 ;
     RECT  46.836 27.203 46.854 27.365 ;
     RECT  49.32 26.825 49.338 27.365 ;
     RECT  0.036 26.905 0.198 27.437 ;
     RECT  18.615 2.413 18.897 27.643 ;
     RECT  7.815 27.301 8.622 27.869 ;
     RECT  1.98 26.813 5.49 27.877 ;
     RECT  18.576 27.643 18.897 28.183 ;
     RECT  1.98 27.877 5.994 28.211 ;
     RECT  0.036 27.437 0.162 28.301 ;
     RECT  0.036 28.301 0.126 29.131 ;
     RECT  0.036 29.131 0.162 29.261 ;
     RECT  18.576 28.183 19.098 29.335 ;
     RECT  1.98 28.211 4.878 29.867 ;
     RECT  0.036 29.261 0.126 30.109 ;
     RECT  0.036 30.109 0.558 30.461 ;
     RECT  2.304 29.867 4.878 30.839 ;
     RECT  1.44 30.685 1.458 30.955 ;
     RECT  18.576 29.335 19.674 31.081 ;
     RECT  4.86 30.839 4.878 31.181 ;
     RECT  2.304 30.839 3.69 31.261 ;
     RECT  2.268 31.261 3.69 31.325 ;
     RECT  2.304 31.325 3.69 31.415 ;
     RECT  0.036 30.461 0.126 31.963 ;
     RECT  2.415 31.415 3.69 32.305 ;
     RECT  2.376 32.305 3.69 32.881 ;
     RECT  2.34 32.881 3.69 33.269 ;
     RECT  34.815 2.413 35.097 33.355 ;
     RECT  2.34 33.269 3.51 33.385 ;
     RECT  34.815 33.355 35.118 33.385 ;
     RECT  35.892 33.241 35.91 33.385 ;
     RECT  2.304 33.385 3.51 33.485 ;
     RECT  34.815 33.385 35.91 33.539 ;
     RECT  30.78 33.355 30.798 33.581 ;
     RECT  34.815 33.539 35.19 33.581 ;
     RECT  1.404 30.955 1.458 33.917 ;
     RECT  2.376 33.485 3.51 34.349 ;
     RECT  0.036 31.963 0.198 35.021 ;
     RECT  2.415 34.349 3.51 35.311 ;
     RECT  2.34 35.311 3.51 35.545 ;
     RECT  2.304 35.545 3.51 35.645 ;
     RECT  16.848 27.203 17.73 35.779 ;
     RECT  18.576 31.081 20.106 35.779 ;
     RECT  1.404 33.917 1.422 36.077 ;
     RECT  2.34 35.645 3.51 36.239 ;
     RECT  2.34 36.239 3.114 36.509 ;
     RECT  0.072 35.021 0.198 37.277 ;
     RECT  0.144 37.277 0.198 37.373 ;
     RECT  30.78 37.327 30.798 37.373 ;
     RECT  32.508 37.429 32.526 37.469 ;
     RECT  0.18 37.373 0.198 37.805 ;
     RECT  2.415 36.509 3.114 38.515 ;
     RECT  5.976 28.211 5.994 38.543 ;
     RECT  2.304 38.515 3.114 38.669 ;
     RECT  2.376 38.669 3.114 38.939 ;
     RECT  0.108 38.137 0.126 39.487 ;
     RECT  2.376 38.939 3.006 39.857 ;
     RECT  2.376 39.857 2.79 40.289 ;
     RECT  2.415 40.289 2.79 40.559 ;
     RECT  0.108 39.487 0.162 40.829 ;
     RECT  0.144 40.829 0.162 41.261 ;
     RECT  26.856 41.179 26.874 41.341 ;
     RECT  26.856 41.341 27.198 41.369 ;
     RECT  27.18 41.369 27.198 41.405 ;
     RECT  16.848 35.779 20.106 46.813 ;
     RECT  16.704 46.813 20.106 46.885 ;
     RECT  16.128 46.885 20.106 47.155 ;
     RECT  3.672 39.865 3.69 47.309 ;
     RECT  15.336 47.155 20.106 47.309 ;
     RECT  15.444 47.309 20.106 47.615 ;
     RECT  24.015 2.413 24.297 47.731 ;
     RECT  4.068 47.461 4.086 47.759 ;
     RECT  23.724 47.731 24.297 47.849 ;
     RECT  22.464 47.323 22.482 47.893 ;
     RECT  23.256 47.857 23.274 47.893 ;
     RECT  15.588 47.615 20.106 48.541 ;
     RECT  22.464 47.893 23.274 48.541 ;
     RECT  25.884 48.469 25.902 48.541 ;
     RECT  34.815 33.581 35.097 48.541 ;
     RECT  22.356 48.541 23.274 48.631 ;
     RECT  24.015 47.849 24.297 48.631 ;
     RECT  34.815 48.541 35.334 48.739 ;
     RECT  15.588 48.541 20.142 48.803 ;
     RECT  15.732 48.803 20.142 48.811 ;
     RECT  29.415 2.413 29.697 48.811 ;
     RECT  31.608 48.775 31.626 48.811 ;
     RECT  34.815 48.739 35.442 48.811 ;
     RECT  36.18 48.667 36.198 48.811 ;
     RECT  15.732 48.811 20.43 48.901 ;
     RECT  21.168 48.811 21.402 48.901 ;
     RECT  31.608 48.811 31.734 48.901 ;
     RECT  15.732 48.901 21.402 48.929 ;
     RECT  31.608 48.901 32.274 48.937 ;
     RECT  33.552 48.739 33.57 48.937 ;
     RECT  25.812 48.541 25.902 48.973 ;
     RECT  25.812 48.973 26.334 49.009 ;
     RECT  25.812 49.009 26.91 49.081 ;
     RECT  29.415 48.811 30.114 49.081 ;
     RECT  25.668 49.081 26.91 49.171 ;
     RECT  29.304 49.081 30.114 49.171 ;
     RECT  31.32 48.937 32.274 49.199 ;
     RECT  22.356 48.631 24.297 49.207 ;
     RECT  25.668 49.171 26.946 49.207 ;
     RECT  31.32 49.199 31.95 49.207 ;
     RECT  31.248 49.207 31.95 49.235 ;
     RECT  22.068 49.207 24.297 49.243 ;
     RECT  25.272 49.207 26.946 49.243 ;
     RECT  22.068 49.243 26.946 49.271 ;
     RECT  29.304 49.171 30.186 49.279 ;
     RECT  33.552 48.937 33.642 49.315 ;
     RECT  34.815 48.811 36.198 49.315 ;
     RECT  31.248 49.235 31.914 49.325 ;
     RECT  29.232 49.279 30.186 49.343 ;
     RECT  29.232 49.343 29.862 49.351 ;
     RECT  2.415 40.559 2.697 49.427 ;
     RECT  7.815 27.869 8.097 49.427 ;
     RECT  13.215 2.413 13.497 49.427 ;
     RECT  40.215 2.413 40.497 49.427 ;
     RECT  45.615 27.203 45.897 49.427 ;
     RECT  15.804 48.929 21.222 49.469 ;
     RECT  27.864 49.045 27.882 49.469 ;
     RECT  29.16 49.351 29.862 49.469 ;
     RECT  33.516 49.315 36.198 49.469 ;
     RECT  29.16 49.469 29.754 49.477 ;
     RECT  33.516 49.469 34.002 49.477 ;
     RECT  15.804 49.469 21.114 49.517 ;
     RECT  29.088 49.477 29.754 49.517 ;
     RECT  26.1 49.271 26.946 49.531 ;
     RECT  31.248 49.325 31.842 49.549 ;
     RECT  20.592 49.517 21.114 49.565 ;
     RECT  22.068 49.271 25.362 49.565 ;
     RECT  29.34 49.517 29.754 49.565 ;
     RECT  33.408 49.477 34.002 49.565 ;
     RECT  34.815 49.469 35.586 49.565 ;
     RECT  16.452 49.517 16.47 49.577 ;
     RECT  17.46 49.517 18.81 49.577 ;
     RECT  22.068 49.565 22.662 49.577 ;
     RECT  23.796 49.565 25.362 49.577 ;
     RECT  26.1 49.531 27.738 49.577 ;
     RECT  29.34 49.565 29.574 49.577 ;
     RECT  36.504 49.531 36.522 49.577 ;
     RECT  20.628 49.565 20.646 49.649 ;
     RECT  2.415 49.427 2.505 49.697 ;
     RECT  7.815 49.427 7.905 49.697 ;
     RECT  13.215 49.427 13.305 49.697 ;
     RECT  18.615 49.577 18.81 49.697 ;
     RECT  23.796 49.577 24.105 49.697 ;
     RECT  29.415 49.577 29.574 49.697 ;
     RECT  34.815 49.565 34.905 49.697 ;
     RECT  40.215 49.427 40.305 49.697 ;
     RECT  45.615 49.427 45.705 49.697 ;
     RECT  18.792 49.697 18.81 49.805 ;
     RECT  29.556 49.697 29.574 49.805 ;
     RECT  22.068 49.577 22.086 50.765 ;
     RECT  23.796 49.697 23.814 50.765 ;
     RECT  25.344 49.577 25.362 50.765 ;
     RECT  31.176 49.549 31.842 50.765 ;
     RECT  33.984 49.565 34.002 50.765 ;
     RECT  26.712 49.577 26.73 51.725 ;
    LAYER M4 ;
     RECT  0.025 12.528 0.06 12.552 ;
     RECT  0.025 34.992 0.06 35.016 ;
     RECT  0.06 10.56 0.137 41.256 ;
     RECT  0.137 23.952 0.173 34.344 ;
     RECT  0.137 35.616 0.173 39.096 ;
     RECT  0.137 40.368 0.173 41.256 ;
     RECT  0.137 13.152 0.209 22.68 ;
     RECT  0.173 27.408 0.209 34.344 ;
     RECT  0.173 37.776 0.209 39.096 ;
     RECT  0.137 10.56 1.433 11.88 ;
     RECT  0.209 14.88 2.293 22.68 ;
     RECT  0.173 23.952 2.293 26.136 ;
     RECT  1.433 10.992 2.408 11.88 ;
     RECT  0.209 13.152 2.408 13.608 ;
     RECT  2.293 14.88 2.408 26.136 ;
     RECT  0.209 27.84 2.408 34.344 ;
     RECT  0.173 35.616 2.408 36.504 ;
     RECT  0.209 38.64 2.408 39.096 ;
     RECT  2.408 2.148 2.512 49.692 ;
     RECT  2.512 2.418 2.704 49.422 ;
     RECT  2.704 19.632 2.765 19.656 ;
     RECT  2.704 13.056 2.837 14.136 ;
     RECT  2.704 15.36 2.845 15.384 ;
     RECT  2.704 16.512 2.953 16.536 ;
     RECT  2.837 13.056 3.017 13.08 ;
     RECT  2.704 22.704 3.089 25.128 ;
     RECT  2.704 26.304 3.197 27.768 ;
     RECT  3.197 26.592 3.233 26.808 ;
     RECT  3.089 22.704 3.269 22.872 ;
     RECT  2.837 14.112 3.299 14.136 ;
     RECT  3.269 22.704 3.341 22.728 ;
     RECT  3.089 23.952 3.413 25.128 ;
     RECT  3.413 24.192 3.449 24.216 ;
     RECT  3.233 26.688 3.881 26.808 ;
     RECT  3.881 26.688 4.241 26.712 ;
     RECT  5.317 26.784 5.573 26.808 ;
     RECT  7.808 2.148 7.912 49.692 ;
     RECT  7.912 2.418 8.104 49.422 ;
     RECT  13.208 2.148 13.312 49.692 ;
     RECT  13.312 2.418 13.504 49.422 ;
     RECT  15.733 49.488 15.793 49.512 ;
     RECT  15.793 48.768 16.441 49.512 ;
     RECT  16.441 48.432 17.42 49.512 ;
     RECT  17.42 48.432 17.845 49.56 ;
     RECT  17.845 47.952 18.385 49.56 ;
     RECT  16.225 27.168 18.608 27.192 ;
     RECT  15.301 37.344 18.608 37.368 ;
     RECT  18.385 47.856 18.608 49.56 ;
     RECT  18.608 2.148 18.712 49.692 ;
     RECT  18.712 2.418 18.737 49.692 ;
     RECT  18.737 2.418 18.821 49.8 ;
     RECT  18.821 2.418 18.904 49.512 ;
     RECT  18.904 47.856 19.091 49.512 ;
     RECT  19.091 48.192 19.217 48.216 ;
     RECT  19.091 49.488 20.365 49.512 ;
     RECT  20.365 49.344 20.531 49.512 ;
     RECT  22.057 50.736 22.259 50.76 ;
     RECT  18.904 27.168 22.499 27.192 ;
     RECT  22.453 47.328 22.537 47.352 ;
     RECT  22.705 48.528 22.853 48.552 ;
     RECT  23.785 50.736 23.987 50.76 ;
     RECT  22.453 33.552 24.008 33.576 ;
     RECT  18.904 37.344 24.008 37.368 ;
     RECT  18.904 41.376 24.008 41.4 ;
     RECT  20.581 49.536 24.008 49.56 ;
     RECT  24.008 2.148 24.112 49.692 ;
     RECT  24.112 2.418 24.304 49.56 ;
     RECT  25.333 50.736 25.715 50.76 ;
     RECT  24.304 49.296 26.147 49.56 ;
     RECT  26.147 49.296 26.305 49.32 ;
     RECT  26.305 49.008 26.579 49.32 ;
     RECT  26.579 49.056 26.669 49.32 ;
     RECT  24.304 41.376 26.845 41.4 ;
     RECT  26.669 49.296 26.957 49.32 ;
     RECT  26.701 51.696 27.011 51.72 ;
     RECT  26.845 41.184 27.209 41.4 ;
     RECT  27.349 49.536 27.875 49.56 ;
     RECT  29.077 49.488 29.125 49.512 ;
     RECT  24.304 33.552 29.408 33.576 ;
     RECT  24.304 37.344 29.408 37.368 ;
     RECT  27.209 41.184 29.408 41.208 ;
     RECT  29.125 49.488 29.408 49.56 ;
     RECT  29.408 2.148 29.512 49.692 ;
     RECT  29.512 2.418 29.545 49.692 ;
     RECT  29.545 2.418 29.629 49.8 ;
     RECT  29.629 2.418 29.704 49.56 ;
     RECT  29.704 49.536 30.035 49.56 ;
     RECT  29.704 33.552 30.769 33.576 ;
     RECT  30.769 33.36 30.809 33.576 ;
     RECT  29.704 37.344 30.809 37.368 ;
     RECT  31.285 49.008 31.372 49.032 ;
     RECT  31.777 49.296 31.925 49.32 ;
     RECT  31.165 50.736 32.195 50.76 ;
     RECT  30.809 33.36 32.389 33.384 ;
     RECT  29.704 41.184 32.435 41.208 ;
     RECT  32.389 37.44 32.537 37.464 ;
     RECT  33.973 50.736 34.355 50.76 ;
     RECT  32.389 33.36 34.808 33.576 ;
     RECT  33.397 49.536 34.808 49.56 ;
     RECT  34.808 2.148 34.912 49.692 ;
     RECT  34.912 2.418 35.104 49.56 ;
     RECT  35.104 33.264 35.201 33.576 ;
     RECT  35.104 49.008 36.083 49.56 ;
     RECT  36.083 49.536 36.533 49.56 ;
     RECT  35.201 33.264 40.208 33.288 ;
     RECT  40.208 2.148 40.312 49.692 ;
     RECT  40.312 2.418 40.504 49.422 ;
     RECT  42.332 26.304 42.373 26.328 ;
     RECT  42.373 25.728 42.419 26.328 ;
     RECT  40.504 33.264 42.419 33.288 ;
     RECT  42.419 25.728 45.529 25.752 ;
     RECT  45.529 25.536 45.608 25.752 ;
     RECT  45.485 26.784 45.608 26.808 ;
     RECT  45.608 2.148 45.712 49.692 ;
     RECT  45.712 2.418 45.904 49.422 ;
     RECT  45.904 25.536 47.149 25.56 ;
     RECT  47.149 25.536 47.173 26.232 ;
     RECT  47.173 25.056 47.219 26.232 ;
     RECT  47.219 26.208 47.233 26.232 ;
     RECT  47.219 25.056 47.26 25.08 ;
     RECT  50.641 26.544 50.677 26.568 ;
     RECT  50.677 24.816 51.804 27 ;
    LAYER M5 ;
     RECT  2.4 2.137 2.52 2.151 ;
     RECT  7.8 2.137 7.92 2.151 ;
     RECT  13.2 2.137 13.32 2.151 ;
     RECT  18.6 2.137 18.72 2.151 ;
     RECT  24 2.137 24.12 2.151 ;
     RECT  29.4 2.137 29.52 2.151 ;
     RECT  34.8 2.137 34.92 2.151 ;
     RECT  40.2 2.137 40.32 2.151 ;
     RECT  45.6 2.137 45.72 2.151 ;
     RECT  2.4 2.151 2.712 13.045 ;
     RECT  2.4 13.045 3 14.101 ;
     RECT  2.4 14.101 3.288 22.021 ;
     RECT  2.304 22.021 3.288 23.315 ;
     RECT  2.4 23.315 3.288 23.987 ;
     RECT  2.4 23.987 3 24.179 ;
     RECT  45.6 2.151 45.912 25.717 ;
     RECT  47.184 25.045 47.208 26.243 ;
     RECT  2.4 24.179 2.904 26.581 ;
     RECT  2.4 26.581 3.144 26.771 ;
     RECT  2.4 26.771 2.904 26.819 ;
     RECT  45.504 25.717 45.912 26.819 ;
     RECT  42.384 25.717 42.408 33.299 ;
     RECT  32.4 33.541 32.424 41.219 ;
     RECT  18.6 2.151 18.912 41.365 ;
     RECT  22.464 27.157 22.488 47.363 ;
     RECT  34.8 2.151 35.112 48.997 ;
     RECT  15.312 37.333 15.336 49.477 ;
     RECT  18.6 41.365 19.08 49.477 ;
     RECT  20.496 49.333 20.52 49.477 ;
     RECT  15.312 49.477 17.064 49.525 ;
     RECT  18.336 49.477 20.52 49.525 ;
     RECT  24 2.151 24.312 49.525 ;
     RECT  26.544 48.997 26.568 49.525 ;
     RECT  29.4 2.151 29.712 49.525 ;
     RECT  34.8 48.997 36.072 49.525 ;
     RECT  2.4 26.819 2.712 49.689 ;
     RECT  7.8 2.151 8.112 49.689 ;
     RECT  13.2 2.151 13.512 49.689 ;
     RECT  40.2 2.151 40.512 49.689 ;
     RECT  45.6 26.819 45.912 49.689 ;
     RECT  2.4 49.689 2.52 49.703 ;
     RECT  7.8 49.689 7.92 49.703 ;
     RECT  13.2 49.689 13.32 49.703 ;
     RECT  33.456 49.525 36.504 49.703 ;
     RECT  40.2 49.689 40.32 49.703 ;
     RECT  45.6 49.689 45.72 49.703 ;
     RECT  31.296 48.997 31.32 50.725 ;
     RECT  33.456 49.703 33.912 50.725 ;
     RECT  15.312 49.525 27.864 51.792 ;
     RECT  29.136 49.525 30.024 51.792 ;
     RECT  31.296 50.725 32.184 51.792 ;
     RECT  33.456 50.725 34.344 51.792 ;
     RECT  35.616 49.703 36.504 51.792 ;
     RECT  45.912 25.045 47.184 26.243 ;
     RECT  22.488 27.157 24 47.363 ;
     RECT  19.08 49.333 20.496 49.477 ;
     RECT  17.064 49.477 18.336 49.525 ;
     RECT  27.864 49.525 29.136 51.708 ;
     RECT  30.024 49.525 31.296 51.708 ;
     RECT  33.912 49.703 35.616 50.725 ;
     RECT  32.184 50.725 33.456 51.708 ;
     RECT  34.344 50.725 35.616 51.708 ;
     RECT  27.912 51.708 28.224 51.792 ;
     RECT  28.344 51.708 28.656 51.792 ;
     RECT  28.776 51.708 29.088 51.792 ;
     RECT  30.072 51.708 30.384 51.792 ;
     RECT  30.504 51.708 30.816 51.792 ;
     RECT  30.936 51.708 31.248 51.792 ;
     RECT  32.232 51.708 32.544 51.792 ;
     RECT  32.664 51.708 32.976 51.792 ;
     RECT  33.096 51.708 33.408 51.792 ;
     RECT  34.392 51.708 34.704 51.792 ;
     RECT  34.824 51.708 35.136 51.792 ;
     RECT  35.256 51.708 35.568 51.792 ;
  END
END dsfd_vm_static_read_v5
END LIBRARY
